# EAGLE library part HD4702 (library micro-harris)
MICROCONTROLLER/MEMORY DEVICE

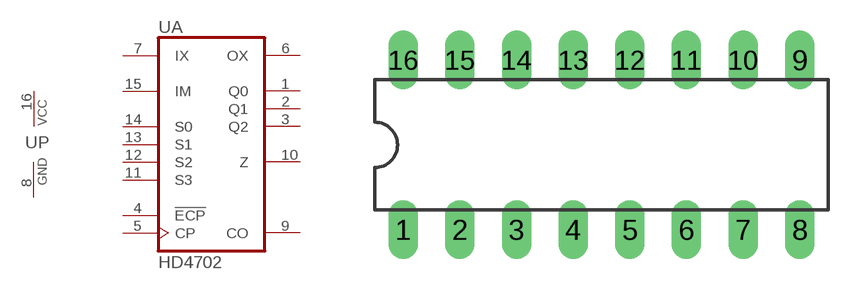
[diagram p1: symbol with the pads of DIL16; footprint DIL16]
Designator prefix U; gates A=HD4702 P=PWRN

## HD4702 (OC_FARNELL: unknown; OC_NEWARK: unknown)  [DIL16]
1  A:Q0  out
2  A:Q1  out
3  A:Q2  out
4  A:!ECP  in
5  A:CP  in
6  A:OX  out
7  A:IX  in
8  P:GND  pwr
9  A:CO  out
10  A:Z  out
11  A:S3  in
12  A:S2  in
13  A:S1  in
14  A:S0  in
15  A:IM  in
16  P:VCC  pwr

## Footprint DIL16 (pad centres in mm)
Dual In Line Package
drill 0.813 long: 1 -8.89,-3.81; 2 -6.35,-3.81; 3 -3.81,-3.81; 4 -1.27,-3.81; 5 1.27,-3.81; 6 3.81,-3.81; 7 6.35,-3.81; 8 8.89,-3.81; 9 8.89,3.81; 10 6.35,3.81; 11 3.81,3.81; 12 1.27,3.81; 13 -1.27,3.81; 14 -3.81,3.81; 15 -6.35,3.81; 16 -8.89,3.81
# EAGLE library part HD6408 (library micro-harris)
MICROCONTROLLER/MEMORY DEVICE

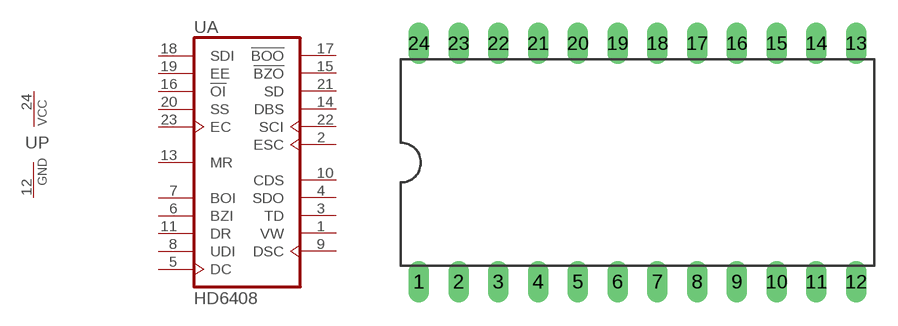
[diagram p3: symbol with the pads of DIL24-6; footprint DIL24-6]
Designator prefix U; gates A=HD6408 P=PWRN

## HD6408 (OC_FARNELL: unknown; OC_NEWARK: unknown)  [DIL24-6]
1  A:VW  out
2  A:ESC  out
3  A:TD  out
4  A:SDO  out
5  A:DC  in
6  A:BZI  in
7  A:BOI  in
8  A:UDI  in
9  A:DSC  out
10  A:CDS  out
11  A:DR  in
12  P:GND  pwr
13  A:MR  in
14  A:DBS  out
15  A:!BZO  hiz
16  A:!OI  in
17  A:!BOO  hiz
18  A:SDI  in
19  A:EE  in
20  A:SS  in
21  A:SD  out
22  A:SCI  out
23  A:EC  in
24  P:VCC  pwr

## Footprint DIL24-6 (pad centres in mm)
Dual In Line Package 0.6 inch
drill 0.813 long: 1 -13.97,-7.62; 2 -11.43,-7.62; 3 -8.89,-7.62; 4 -6.35,-7.62; 5 -3.81,-7.62; 6 -1.27,-7.62; 7 1.27,-7.62; 8 3.81,-7.62; 9 6.35,-7.62; 10 8.89,-7.62; 11 11.43,-7.62; 12 13.97,-7.62; 13 13.97,7.62; 14 11.43,7.62; 15 8.89,7.62; 16 6.35,7.62; 17 3.81,7.62; 18 1.27,7.62; 19 -1.27,7.62; 20 -3.81,7.62; 21 -6.35,7.62; 22 -8.89,7.62; 23 -11.43,7.62; 24 -13.97,7.62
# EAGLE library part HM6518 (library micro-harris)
MICROCONTROLLER/MEMORY DEVICE

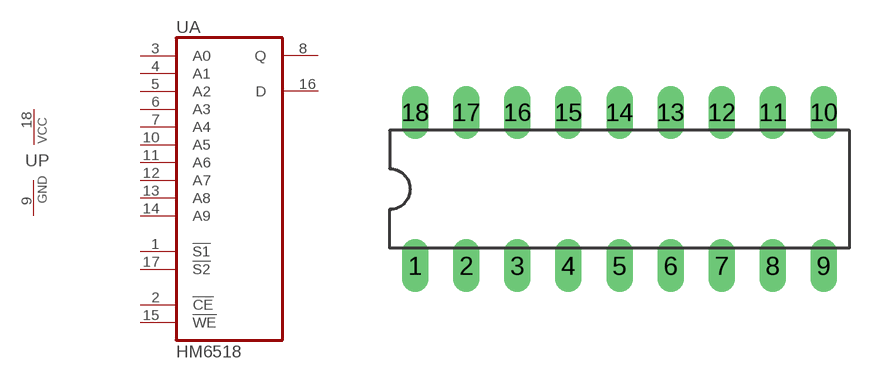
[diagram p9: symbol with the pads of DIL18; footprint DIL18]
Designator prefix U; gates A=HM6518 P=PWRN

## HM6518 (OC_FARNELL: unknown; OC_NEWARK: unknown)  [DIL18]
1  A:!S1  in
2  A:!CE  in
3  A:A0  in
4  A:A1  in
5  A:A2  in
6  A:A3  in
7  A:A4  in
8  A:Q  hiz
9  P:GND  pwr
10  A:A5  in
11  A:A6  in
12  A:A7  in
13  A:A8  in
14  A:A9  in
15  A:!WE  in
16  A:D  in
17  A:!S2  in
18  P:VCC  pwr

## Footprint DIL18 (pad centres in mm)
Dual In Line Package
drill 0.813 long: 1 -10.16,-3.81; 2 -7.62,-3.81; 3 -5.08,-3.81; 4 -2.54,-3.81; 5 0,-3.81; 6 2.54,-3.81; 7 5.08,-3.81; 8 7.62,-3.81; 9 10.16,-3.81; 10 10.16,3.81; 11 7.62,3.81; 12 5.08,3.81; 13 2.54,3.81; 14 0,3.81; 15 -2.54,3.81; 16 -5.08,3.81; 17 -7.62,3.81; 18 -10.16,3.81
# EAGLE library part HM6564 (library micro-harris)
MICROCONTROLLER/MEMORY DEVICE

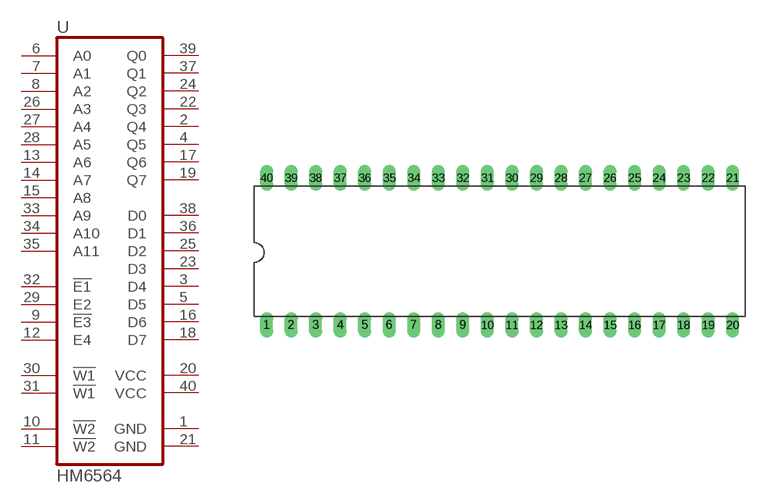
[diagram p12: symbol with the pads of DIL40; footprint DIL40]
Designator prefix U

## HM6564 (OC_FARNELL: unknown; OC_NEWARK: unknown)  [DIL40]
1  GND  pwr
2  Q4  hiz
3  D4  in
4  Q5  hiz
5  D5  in
6  A0  in
7  A1  in
8  A2  in
9  !E3  in
10  !W2  in
11  !W2  in
12  E4  in
13  A6  in
14  A7  in
15  A8  in
16  D6  in
17  Q6  hiz
18  D7  in
19  Q7  hiz
20  VCC  pwr
21  GND  pwr
22  Q3  hiz
23  D3  in
24  Q2  hiz
25  D2  in
26  A3  in
27  A4  in
28  A5  in
29  E2  in
30  !W1  in
31  !W1  in
32  !E1  in
33  A9  in
34  A10  in
35  A11  in
36  D1  in
37  Q1  hiz
38  D0  in
39  Q0  hiz
40  VCC  pwr

## Footprint DIL40 (pad centres in mm)
Dual In Line Package
drill 0.813 long: 1 -24.13,-7.62; 2 -21.59,-7.62; 3 -19.05,-7.62; 4 -16.51,-7.62; 5 -13.97,-7.62; 6 -11.43,-7.62; 7 -8.89,-7.62; 8 -6.35,-7.62; 9 -3.81,-7.62; 10 -1.27,-7.62; 11 1.27,-7.62; 12 3.81,-7.62; 13 6.35,-7.62; 14 8.89,-7.62; 15 11.43,-7.62; 16 13.97,-7.62; 17 16.51,-7.62; 18 19.05,-7.62; 19 21.59,-7.62; 20 24.13,-7.62; 21 24.13,7.62; 22 21.59,7.62; 23 19.05,7.62; 24 16.51,7.62; 25 13.97,7.62; 26 11.43,7.62; 27 8.89,7.62; 28 6.35,7.62; 29 3.81,7.62; 30 1.27,7.62; 31 -1.27,7.62; 32 -3.81,7.62; 33 -6.35,7.62; 34 -8.89,7.62; 35 -11.43,7.62; 36 -13.97,7.62; 37 -16.51,7.62; 38 -19.05,7.62; 39 -21.59,7.62; 40 -24.13,7.62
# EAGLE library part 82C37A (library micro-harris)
MICROCONTROLLER/MEMORY DEVICE

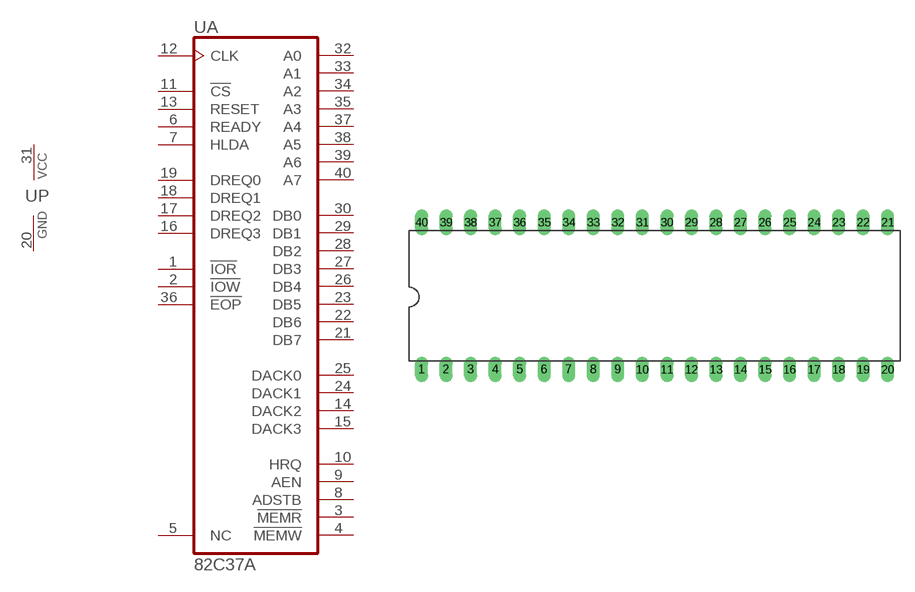
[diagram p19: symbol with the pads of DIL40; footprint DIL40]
Designator prefix U; gates A=82C37A P=PWRN

## 82C37A (OC_FARNELL: unknown; OC_NEWARK: unknown)  [DIL40]
1  A:!IOR
2  A:!IOW
3  A:!MEMR  out
4  A:!MEMW  out
5  A:NC  nc
6  A:READY  in
7  A:HLDA  in
8  A:ADSTB  out
9  A:AEN  out
10  A:HRQ  out
11  A:!CS  in
12  A:CLK  in
13  A:RESET  in
14  A:DACK2  out
15  A:DACK3  out
16  A:DREQ3  in
17  A:DREQ2  in
18  A:DREQ1  in
19  A:DREQ0  in
20  P:GND  pwr
21  A:DB7
22  A:DB6
23  A:DB5
24  A:DACK1  out
25  A:DACK0  out
26  A:DB4
27  A:DB3
28  A:DB2
29  A:DB1
30  A:DB0
31  P:VCC  pwr
32  A:A0
33  A:A1
34  A:A2
35  A:A3
36  A:!EOP
37  A:A4  out
38  A:A5  out
39  A:A6  out
40  A:A7  out

## Footprint DIL40 (pad centres in mm)
Dual In Line Package
drill 0.813 long: 1 -24.13,-7.62; 2 -21.59,-7.62; 3 -19.05,-7.62; 4 -16.51,-7.62; 5 -13.97,-7.62; 6 -11.43,-7.62; 7 -8.89,-7.62; 8 -6.35,-7.62; 9 -3.81,-7.62; 10 -1.27,-7.62; 11 1.27,-7.62; 12 3.81,-7.62; 13 6.35,-7.62; 14 8.89,-7.62; 15 11.43,-7.62; 16 13.97,-7.62; 17 16.51,-7.62; 18 19.05,-7.62; 19 21.59,-7.62; 20 24.13,-7.62; 21 24.13,7.62; 22 21.59,7.62; 23 19.05,7.62; 24 16.51,7.62; 25 13.97,7.62; 26 11.43,7.62; 27 8.89,7.62; 28 6.35,7.62; 29 3.81,7.62; 30 1.27,7.62; 31 -1.27,7.62; 32 -3.81,7.62; 33 -6.35,7.62; 34 -8.89,7.62; 35 -11.43,7.62; 36 -13.97,7.62; 37 -16.51,7.62; 38 -19.05,7.62; 39 -21.59,7.62; 40 -24.13,7.62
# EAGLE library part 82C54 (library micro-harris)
MICROCONTROLLER/MEMORY DEVICE

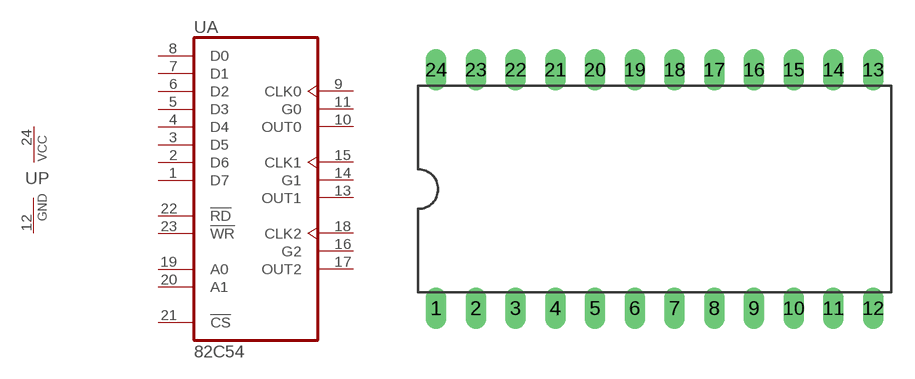
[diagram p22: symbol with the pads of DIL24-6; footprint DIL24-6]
Designator prefix U; gates A=82C54 P=PWRN

## 82C54 (MF: INTERSIL; MPN: CP82C54Z; OC_FARNELL: 1018175; OC_NEWARK: 57K3037)  [DIL24-6]
1  A:D7
2  A:D6
3  A:D5
4  A:D4
5  A:D3
6  A:D2
7  A:D1
8  A:D0
9  A:CLK0  in
10  A:OUT0  out
11  A:G0  in
12  P:GND  pwr
13  A:OUT1  out
14  A:G1  in
15  A:CLK1  in
16  A:G2  in
17  A:OUT2  out
18  A:CLK2  in
19  A:A0  in
20  A:A1  in
21  A:!CS  in
22  A:!RD  in
23  A:!WR  in
24  P:VCC  pwr

## Footprint DIL24-6 (pad centres in mm)
Dual In Line Package 0.6 inch
drill 0.813 long: 1 -13.97,-7.62; 2 -11.43,-7.62; 3 -8.89,-7.62; 4 -6.35,-7.62; 5 -3.81,-7.62; 6 -1.27,-7.62; 7 1.27,-7.62; 8 3.81,-7.62; 9 6.35,-7.62; 10 8.89,-7.62; 11 11.43,-7.62; 12 13.97,-7.62; 13 13.97,7.62; 14 11.43,7.62; 15 8.89,7.62; 16 6.35,7.62; 17 3.81,7.62; 18 1.27,7.62; 19 -1.27,7.62; 20 -3.81,7.62; 21 -6.35,7.62; 22 -8.89,7.62; 23 -11.43,7.62; 24 -13.97,7.62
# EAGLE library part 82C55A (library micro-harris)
MICROCONTROLLER/MEMORY DEVICE

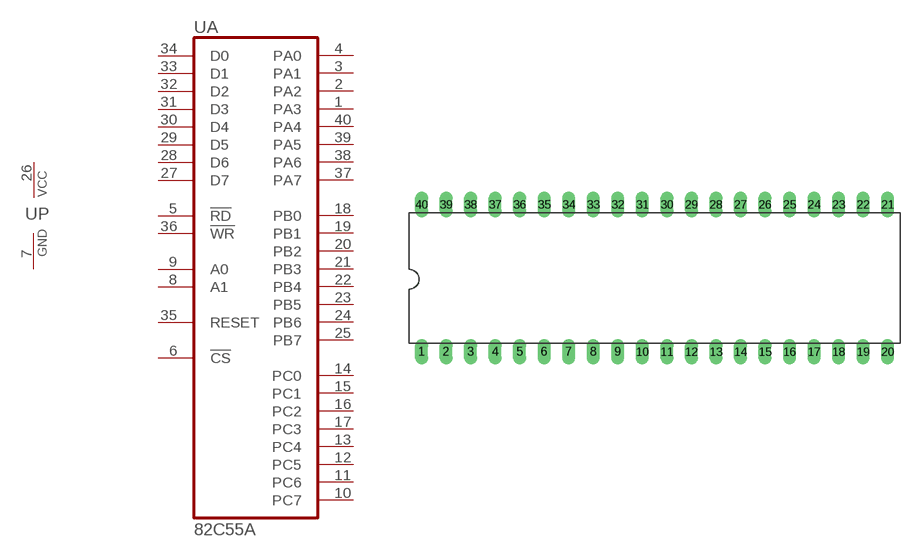
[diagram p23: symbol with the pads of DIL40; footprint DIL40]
Designator prefix U; gates A=82C55A P=PWRN

## 82C55A (MF: INTERSIL; MPN: CP82C55A-5; OC_FARNELL: 1018158; OC_NEWARK: 06F3290)  [DIL40]
1  A:PA3
2  A:PA2
3  A:PA1
4  A:PA0
5  A:!RD  in
6  A:!CS  in
7  P:GND  pwr
8  A:A1  in
9  A:A0  in
10  A:PC7
11  A:PC6
12  A:PC5
13  A:PC4
14  A:PC0
15  A:PC1
16  A:PC2
17  A:PC3
18  A:PB0
19  A:PB1
20  A:PB2
21  A:PB3
22  A:PB4
23  A:PB5
24  A:PB6
25  A:PB7
26  P:VCC  pwr
27  A:D7
28  A:D6
29  A:D5
30  A:D4
31  A:D3
32  A:D2
33  A:D1
34  A:D0
35  A:RESET  in
36  A:!WR  in
37  A:PA7
38  A:PA6
39  A:PA5
40  A:PA4

## Footprint DIL40 (pad centres in mm)
Dual In Line Package
drill 0.813 long: 1 -24.13,-7.62; 2 -21.59,-7.62; 3 -19.05,-7.62; 4 -16.51,-7.62; 5 -13.97,-7.62; 6 -11.43,-7.62; 7 -8.89,-7.62; 8 -6.35,-7.62; 9 -3.81,-7.62; 10 -1.27,-7.62; 11 1.27,-7.62; 12 3.81,-7.62; 13 6.35,-7.62; 14 8.89,-7.62; 15 11.43,-7.62; 16 13.97,-7.62; 17 16.51,-7.62; 18 19.05,-7.62; 19 21.59,-7.62; 20 24.13,-7.62; 21 24.13,7.62; 22 21.59,7.62; 23 19.05,7.62; 24 16.51,7.62; 25 13.97,7.62; 26 11.43,7.62; 27 8.89,7.62; 28 6.35,7.62; 29 3.81,7.62; 30 1.27,7.62; 31 -1.27,7.62; 32 -3.81,7.62; 33 -6.35,7.62; 34 -8.89,7.62; 35 -11.43,7.62; 36 -13.97,7.62; 37 -16.51,7.62; 38 -19.05,7.62; 39 -21.59,7.62; 40 -24.13,7.62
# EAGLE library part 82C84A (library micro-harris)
MICROCONTROLLER/MEMORY DEVICE

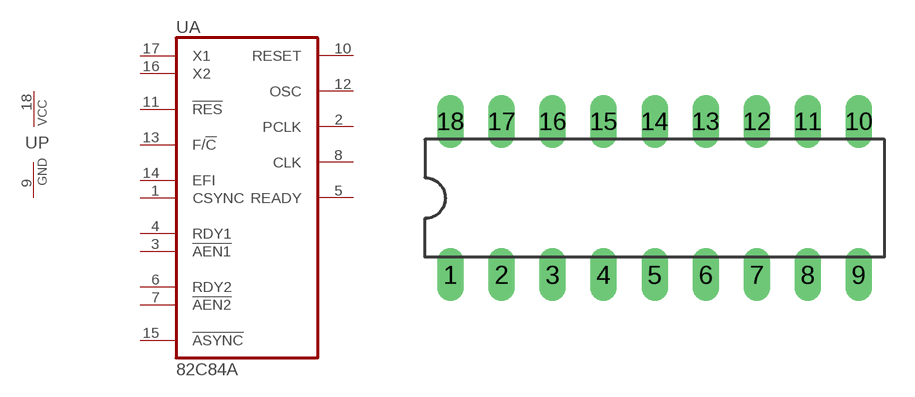
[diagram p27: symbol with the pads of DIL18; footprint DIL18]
Designator prefix U; gates A=82C84A P=PWRN

## 82C84A (MF: INTERSIL; MPN: CP82C84AZ; OC_FARNELL: 1216116; OC_NEWARK: 79K6037)  [DIL18]
1  A:CSYNC  in
2  A:PCLK  out
3  A:!AEN1  in
4  A:RDY1  in
5  A:READY  out
6  A:RDY2  in
7  A:!AEN2  in
8  A:CLK  out
9  P:GND  pwr
10  A:RESET  out
11  A:!RES  in
12  A:OSC  out
13  A:F/!C  in
14  A:EFI  in
15  A:!ASYNC  in
16  A:X2  out
17  A:X1  in
18  P:VCC  pwr

## Footprint DIL18 (pad centres in mm)
Dual In Line Package
drill 0.813 long: 1 -10.16,-3.81; 2 -7.62,-3.81; 3 -5.08,-3.81; 4 -2.54,-3.81; 5 0,-3.81; 6 2.54,-3.81; 7 5.08,-3.81; 8 7.62,-3.81; 9 10.16,-3.81; 10 10.16,3.81; 11 7.62,3.81; 12 5.08,3.81; 13 2.54,3.81; 14 0,3.81; 15 -2.54,3.81; 16 -5.08,3.81; 17 -7.62,3.81; 18 -10.16,3.81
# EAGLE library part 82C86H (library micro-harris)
MICROCONTROLLER/MEMORY DEVICE

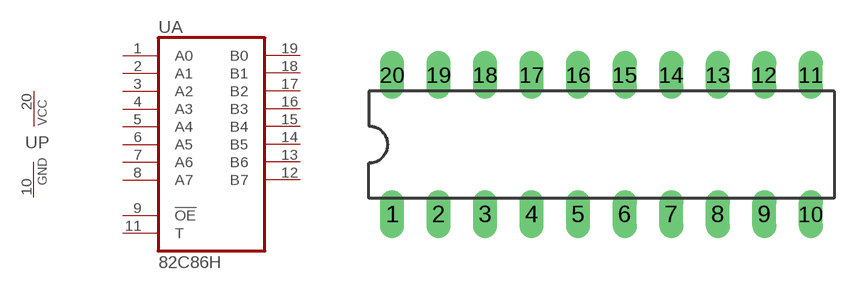
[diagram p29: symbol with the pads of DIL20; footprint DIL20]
Designator prefix U; gates A=82C86H P=PWRN

## 82C86H (MF: INTERSIL; MPN: ID82C86H; OC_FARNELL: unknown; OC_NEWARK: 05B7338)  [DIL20]
1  A:A0
2  A:A1
3  A:A2
4  A:A3
5  A:A4
6  A:A5
7  A:A6
8  A:A7
9  A:!OE  in
10  P:GND  pwr
11  A:T  in
12  A:B7
13  A:B6
14  A:B5
15  A:B4
16  A:B3
17  A:B2
18  A:B1
19  A:B0
20  P:VCC  pwr

## Footprint DIL20 (pad centres in mm)
Dual In Line Package
drill 0.813 long: 1 -11.43,-3.81; 2 -8.89,-3.81; 3 -6.35,-3.81; 4 -3.81,-3.81; 5 -1.27,-3.81; 6 1.27,-3.81; 7 3.81,-3.81; 8 6.35,-3.81; 9 8.89,-3.81; 10 11.43,-3.81; 11 11.43,3.81; 12 8.89,3.81; 13 6.35,3.81; 14 3.81,3.81; 15 1.27,3.81; 16 -1.27,3.81; 17 -3.81,3.81; 18 -6.35,3.81; 19 -8.89,3.81; 20 -11.43,3.81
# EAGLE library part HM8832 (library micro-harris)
MICROCONTROLLER/MEMORY DEVICE

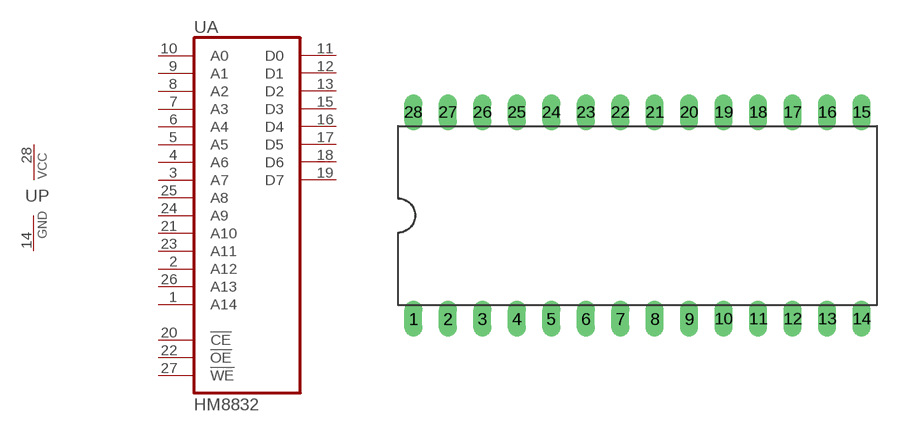
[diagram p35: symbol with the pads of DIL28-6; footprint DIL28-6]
Designator prefix U; gates A=HM8832 P=PWRN

## HM8832 (OC_FARNELL: unknown; OC_NEWARK: unknown)  [DIL28-6]
1  A:A14  in
2  A:A12  in
3  A:A7  in
4  A:A6  in
5  A:A5  in
6  A:A4  in
7  A:A3  in
8  A:A2  in
9  A:A1  in
10  A:A0  in
11  A:D0
12  A:D1
13  A:D2
14  P:GND  pwr
15  A:D3
16  A:D4
17  A:D5
18  A:D6
19  A:D7
20  A:!CE  in
21  A:A10  in
22  A:!OE  in
23  A:A11  in
24  A:A9  in
25  A:A8  in
26  A:A13  in
27  A:!WE  in
28  P:VCC  pwr

## Footprint DIL28-6 (pad centres in mm)
Dual In Line Package 0.6 inch
drill 0.813 long: 1 -16.51,-7.62; 2 -13.97,-7.62; 3 -11.43,-7.62; 4 -8.89,-7.62; 5 -6.35,-7.62; 6 -3.81,-7.62; 7 -1.27,-7.62; 8 1.27,-7.62; 9 3.81,-7.62; 10 6.35,-7.62; 11 8.89,-7.62; 12 11.43,-7.62; 13 13.97,-7.62; 14 16.51,-7.62; 15 16.51,7.62; 16 13.97,7.62; 17 11.43,7.62; 18 8.89,7.62; 19 6.35,7.62; 20 3.81,7.62; 21 1.27,7.62; 22 -1.27,7.62; 23 -3.81,7.62; 24 -6.35,7.62; 25 -8.89,7.62; 26 -11.43,7.62; 27 -13.97,7.62; 28 -16.51,7.62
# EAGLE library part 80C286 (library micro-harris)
MICROCONTROLLER/MEMORY DEVICE

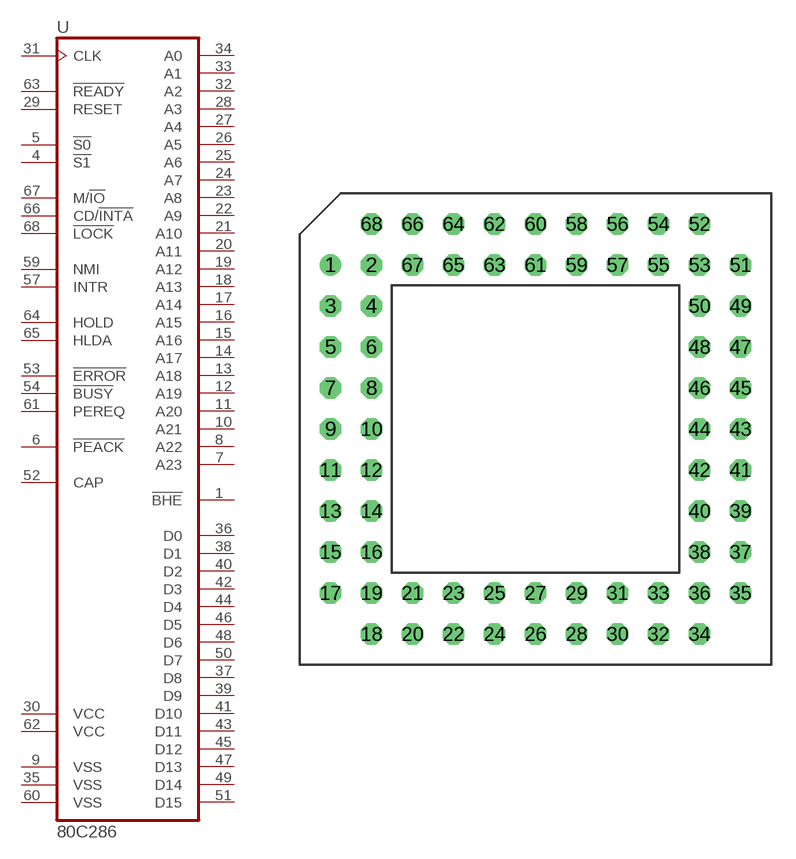
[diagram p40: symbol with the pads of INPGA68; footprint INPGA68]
Designator prefix U

## 80C286 (OC_FARNELL: unknown; OC_NEWARK: unknown)  [INPGA68]
1  !BHE  out
4  !S1  out
5  !S0  out
6  !PEACK  out
7  A23  out
8  A22  out
9  VSS  pwr
10  A21  out
11  A20  out
12  A19  out
13  A18  out
14  A17  out
15  A16  out
16  A15  out
17  A14  out
18  A13  out
19  A12  out
20  A11  out
21  A10  out
22  A9  out
23  A8  out
24  A7  out
25  A6  out
26  A5  out
27  A4  out
28  A3  out
29  RESET  in
30  VCC  pwr
31  CLK  in
32  A2  out
33  A1  out
34  A0  out
35  VSS  pwr
36  D0
37  D8
38  D1
39  D9
40  D2
41  D10
42  D3
43  D11
44  D4
45  D12
46  D5
47  D13
48  D6
49  D14
50  D7
51  D15
52  CAP  in
53  !ERROR  in
54  !BUSY  in
57  INTR  in
59  NMI  in
60  VSS  pwr
61  PEREQ  in
62  VCC  pwr
63  !READY  in
64  HOLD  in
65  HLDA  out
66  CD/!INTA  out
67  M/!IO  out
68  !LOCK  out

## Footprint INPGA68 (pad centres in mm)
Pin Grid Array
drill 0.813 round: 1 -12.7,10.16
drill 0.813 octagon: 2 -10.16,10.16; 3 -12.7,7.62; 4 -10.16,7.62; 5 -12.7,5.08; 6 -10.16,5.08; 7 -12.7,2.54; 8 -10.16,2.54; 9 -12.7,0; 10 -10.16,0; 11 -12.7,-2.54; 12 -10.16,-2.54; 13 -12.7,-5.08; 14 -10.16,-5.08; 15 -12.7,-7.62; 16 -10.16,-7.62; 17 -12.7,-10.16; 18 -10.16,-12.7; 19 -10.16,-10.16; 20 -7.62,-12.7; 21 -7.62,-10.16; 22 -5.08,-12.7; 23 -5.08,-10.16; 24 -2.54,-12.7; 25 -2.54,-10.16; 26 0,-12.7; 27 0,-10.16; 28 2.54,-12.7; 29 2.54,-10.16; 30 5.08,-12.7; 31 5.08,-10.16; 32 7.62,-12.7; 33 7.62,-10.16; 34 10.16,-12.7; 35 12.7,-10.16; 36 10.16,-10.16; 37 12.7,-7.62; 38 10.16,-7.62; 39 12.7,-5.08; 40 10.16,-5.08; 41 12.7,-2.54; 42 10.16,-2.54; 43 12.7,0; 44 10.16,0; 45 12.7,2.54; 46 10.16,2.54; 47 12.7,5.08; 48 10.16,5.08; 49 12.7,7.62; 50 10.16,7.62; 51 12.7,10.16; 52 10.16,12.7; 53 10.16,10.16; 54 7.62,12.7; 55 7.62,10.16; 56 5.08,12.7; 57 5.08,10.16; 58 2.54,12.7; 59 2.54,10.16; 60 0,12.7; 61 0,10.16; 62 -2.54,12.7; 63 -2.54,10.16; 64 -5.08,12.7; 65 -5.08,10.16; 66 -7.62,12.7; 67 -7.62,10.16; 68 -10.16,12.7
